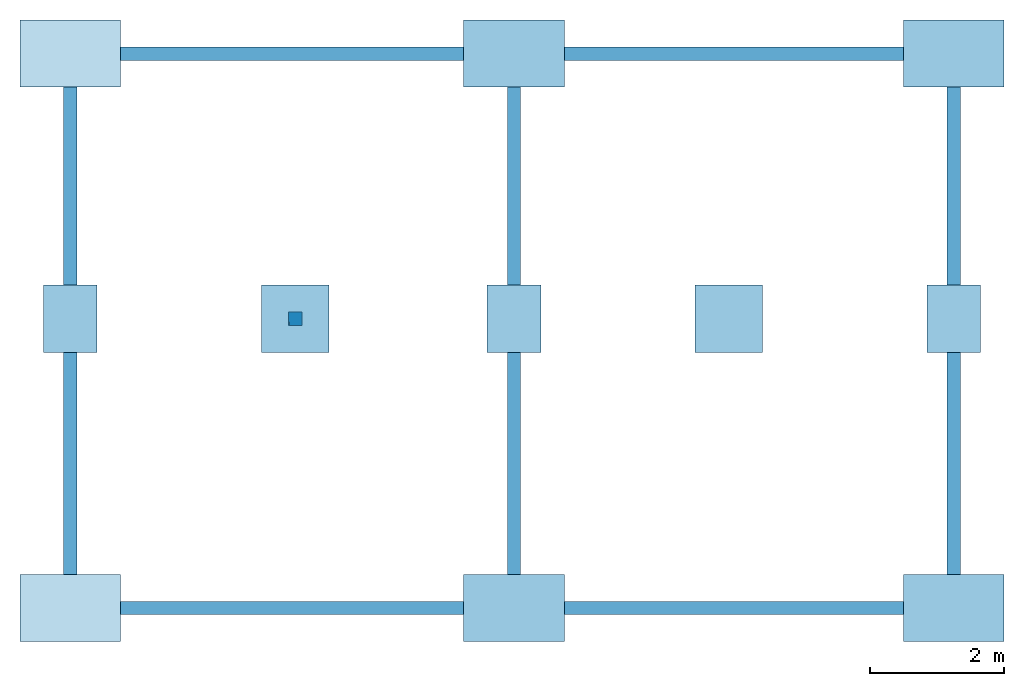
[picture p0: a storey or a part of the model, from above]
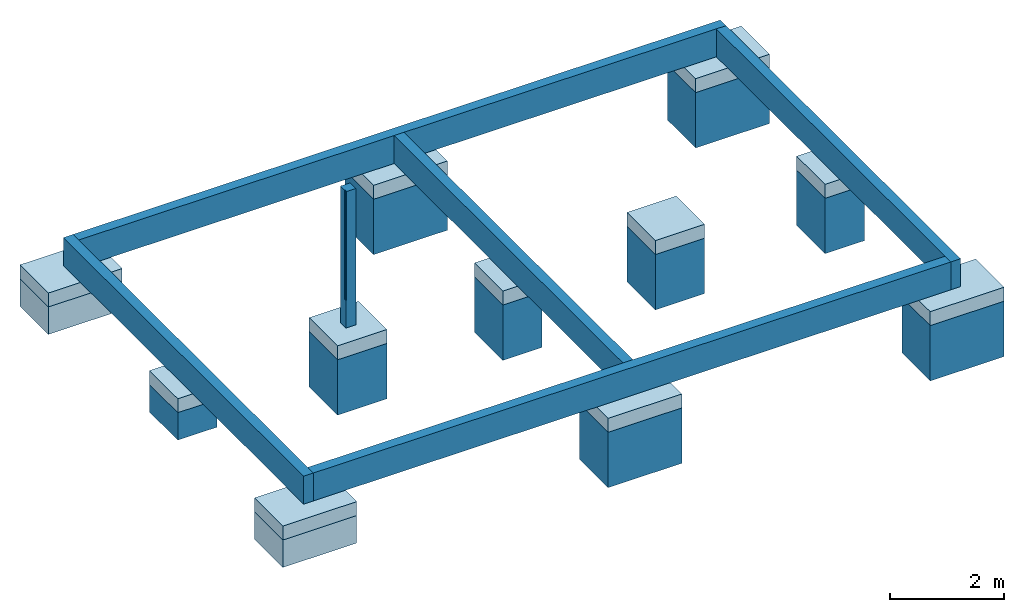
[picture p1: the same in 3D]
Properties of the parts of a building model (IFC2X3)

# File
Description: ViewDefinition [CoordinationView]
Time: 2021-03-23T14:54:17
Made in: SketchUp Pro 2015

# IfcProject, Default Project
Description: Description of Default Project

# IfcSite, Surface:187648
Description: Description of Object; RefLatitude: 24, 28, 0; RefLongitude: 54, 25, 0; RefElevation: 10 mm
Generic - Name: S; CompositionType: c

# IfcBuilding, Default Building
Description: Description of Default Building

# IfcBuildingStorey (4)
In: Default Building
Description: Description of Default Building Storey; Elevation: 0 mm
Name
Plan de couverture
Plan étage
Rez de chaussée
soubassement

# IfcBeam (2)
In: Rez de chaussée
Description: Description of Object
ObjectType - IfcLabel: Poutre rectangulaire - Béton:200 x 400 mm:273551
PSet_BeamCommon - Reference: 200 x 400 mm; Span: 6.53; Slope: 0; isExternal: no; isLoadBearing: yes
Name (IfcBeam - Poutre rectangulaire - Béton:200 x 400 mm:...) | IfcLabel
275096 | Poutre rectangulaire - Béton:200 x 400 mm:275096
274924 | Poutre rectangulaire - Béton:200 x 400 mm:274924

# IfcBuildingElementProxy, IfcBuildingElementProxy - Plafond composé:Plafond avec isolation:277230
In: Plan étage
Description: Description of Object
CompositionType - IfcElementCompositionEnum: complex
ObjectType - IfcLabel: Plafond composé:Plafond avec isolation
Name - IfcLabel: Plafond composé:Plafond avec isolation:277230
Pset_CoveringCommon - Reference: Plafond avec isolation; TotalThickness: 260

# IfcColumn (2)
Description: Description of Object
ObjectType - IfcLabel: 200 x 200 mm
PSet_ColumnCommon - Reference: 200 x 200 mm; isExternal: no; isLoadBearing: no
Name (IfcColumn - Poteau rectangulaire:200 x 200 mm:...) | In | IfcLabel
187492 | Rez de chaussée | Poteau rectangulaire:200 x 200 mm:187492
187471 | soubassement | Poteau rectangulaire:200 x 200 mm:187471

# IfcDoor (26)
Description: Description of Object
PSet_DoorCommon - isExternal: no
Name | In | ObjectType, IfcLabel = Reference | Name, IfcLabel
IfcDoor - Int. Simple:PP (0.83m x 2.04m):187647 | Plan étage | PP (0.83m x 2.04m) | Int. Simple:PP (0.83m x 2.04m):187647
IfcDoor - Int. Simple:PP (0.83m x 2.04m):187644 | Plan étage | PP (0.83m x 2.04m) | Int. Simple:PP (0.83m x 2.04m):187644
IfcDoor - Int. Simple:PP (0.83m x 2.04m):187641 | Plan étage | PP (0.83m x 2.04m) | Int. Simple:PP (0.83m x 2.04m):187641
IfcDoor - Int. Simple:PP (0.83m x 2.04m):187636 | Plan étage | PP (0.83m x 2.04m) | Int. Simple:PP (0.83m x 2.04m):187636
IfcDoor - Int. Simple:PP (0.83m x 2.04m):187635 | Plan étage | PP (0.83m x 2.04m) | Int. Simple:PP (0.83m x 2.04m):187635
IfcDoor - Int. Simple:PP (0.83m x 2.04m):187633 | Plan étage | PP (0.83m x 2.04m) | Int. Simple:PP (0.83m x 2.04m):187633
IfcDoor - Int. Simple:PP (0.83m x 2.04m):187632 | Plan étage | PP (0.83m x 2.04m) | Int. Simple:PP (0.83m x 2.04m):187632
IfcDoor - Int. Simple:PP (0.83m x 2.04m):187631 | Plan étage | PP (0.83m x 2.04m) | Int. Simple:PP (0.83m x 2.04m):187631
IfcDoor - Int. Simple:PP (0.83m x 2.04m):187630 | Plan étage | PP (0.83m x 2.04m) | Int. Simple:PP (0.83m x 2.04m):187630
IfcDoor - Int. Simple:PP (0.83m x 2.04m):187629 | Plan étage | PP (0.83m x 2.04m) | Int. Simple:PP (0.83m x 2.04m):187629
IfcDoor - Int. Simple:PP (0.83m x 2.04m):206630 | Rez de chaussée | PP (0.83m x 2.04m) | Int. Simple:PP (0.83m x 2.04m):206630
IfcDoor - Int. Simple:PP (0.83m x 2.04m):206587 | Rez de chaussée | PP (0.83m x 2.04m) | Int. Simple:PP (0.83m x 2.04m):206587
IfcDoor - Int. Simple:PP (0.83m x 2.04m):206556 | Rez de chaussée | PP (0.83m x 2.04m) | Int. Simple:PP (0.83m x 2.04m):206556
IfcDoor - Int. Simple:PP (0.83m x 2.04m):206517 | Rez de chaussée | PP (0.83m x 2.04m) | Int. Simple:PP (0.83m x 2.04m):206517
IfcDoor - Int. Simple:PP (0.83m x 2.04m):206475 | Rez de chaussée | PP (0.83m x 2.04m) | Int. Simple:PP (0.83m x 2.04m):206475
IfcDoor - Int. Simple:PP (0.83m x 2.04m):206419 | Rez de chaussée | PP (0.83m x 2.04m) | Int. Simple:PP (0.83m x 2.04m):206419
IfcDoor - Double-Glass 1_no trim:PF 1.30 x 2.15:206001 | Rez de chaussée | PF 1.30 x 2.15 | Double-Glass 1_no trim:PF 1.30 x 2.15:206001
IfcDoor - Double-Glass 1_no trim:PF 1.30 x 2.15:205958 | Rez de chaussée | PF 1.30 x 2.15 | Double-Glass 1_no trim:PF 1.30 x 2.15:205958
IfcDoor - Double-Glass 1_no trim:PF 1.30 x 2.15:205926 | Rez de chaussée | PF 1.30 x 2.15 | Double-Glass 1_no trim:PF 1.30 x 2.15:205926
IfcDoor - Double-Glass 1_no trim:PF 1.30 x 2.15:205899 | Rez de chaussée | PF 1.30 x 2.15 | Double-Glass 1_no trim:PF 1.30 x 2.15:205899
IfcDoor - Porte d'entrée:PP Lisse (0.90m x 2.15m):205515 | Rez de chaussée | PP Lisse (0.90m x 2.15m) | Porte d'entrée:PP Lisse (0.90m x 2.15m):205515
IfcDoor - Double-Glass 1_no trim:PF 1.60 x 2.15:205435 | Rez de chaussée | PF 1.60 x 2.15 | Double-Glass 1_no trim:PF 1.60 x 2.15:205435
IfcDoor - Double-Glass 1_no trim:PF 1.60 x 2.15:205161 | Rez de chaussée | PF 1.60 x 2.15 | Double-Glass 1_no trim:PF 1.60 x 2.15:205161
IfcDoor - Placard coulissante - 3 panneaux:Placard coulissante - 3 panneaux:204080 | Rez de chaussée | Placard coulissante - 3 panneaux | Placard coulissante - 3 panneaux:Placard coulissante - 3 panneaux:204080
IfcDoor - Placard coulissante - 3 panneaux:Placard coulissante - 3 panneaux:187537 | Rez de chaussée | Placard coulissante - 3 panneaux | Placard coulissante - 3 panneaux:Placard coulissante - 3 panneaux:187537
IfcDoor - Porte d'entrée:PP Lisse (0.90m x 2.15m):187528 | Rez de chaussée | PP Lisse (0.90m x 2.15m) | Porte d'entrée:PP Lisse (0.90m x 2.15m):187528

# IfcRailing (3)
In: Rez de chaussée
Description: Description of Object
PredefinedType - IfcRailingTypeEnum: handrail
ObjectType - IfcLabel: Garde-corps:Type Bateau
PSet_RailingCommon - Reference: Type Bateau; isExternal: no
Name (IfcRailing - Garde-corps:Type Bateau:...) | IfcLabel
271948 | Garde-corps:Type Bateau:271948
227138 | Garde-corps:Type Bateau:227138
223490 | Garde-corps:Type Bateau:223490

# IfcSlab (27)
Description: Description of Object
PredefinedType - IfcSlabTypeEnum: floor
PSet_SlabCommon - isLoadBearing: yes
Name | In | ObjectType, IfcLabel | Name, IfcLabel | Reference | PitchAngle | isExternal
2 x IfcSlab - Toit de base:Toit - 200 mm:277896 | Plan de couverture | Toit de base:Toit - 200 mm | Toit de base:Toit - 200 mm:277896 | Toit - 200 mm | 31 | yes
IfcSlab - Sol:Dalle Béton -160 + 60 mm:276078 | Plan étage | Sol:Dalle Béton -160 + 60 mm | Sol:Dalle Béton -160 + 60 mm:276078 | Dalle Béton -160 + 60 mm | 0 | no
IfcSlab - Sol:Dalle en béton - 13:220152 | Rez de chaussée | Sol:Dalle en béton - 13 | Sol:Dalle en béton - 13:220152 | Dalle en béton - 13 | 0 | no
IfcSlab - Sol:Dalle en béton - 13:219665 | Rez de chaussée | Sol:Dalle en béton - 13 | Sol:Dalle en béton - 13:219665 | Dalle en béton - 13 | 0 | no
IfcSlab - Base rectangulaire:gros beton 1000mm x 800mm x 1190mm:218905 | soubassement | Base rectangulaire:gros beton 1000mm x 800mm x 1190mm | Base rectangulaire:gros beton 1000mm x 800mm x 1190mm:218905 | gros beton 1000mm x 800mm x 1190mm | 0 | no
IfcSlab - Base rectangulaire:gros beton 1000mm x 800mm x 1190mm:218791 | soubassement | Base rectangulaire:gros beton 1000mm x 800mm x 1190mm | Base rectangulaire:gros beton 1000mm x 800mm x 1190mm:218791 | gros beton 1000mm x 800mm x 1190mm | 0 | no
IfcSlab - Base rectangulaire:gros beton 1000mm x 800mm x 590mm:218621 | soubassement | Base rectangulaire:gros beton 1000mm x 800mm x 590mm | Base rectangulaire:gros beton 1000mm x 800mm x 590mm:218621 | gros beton 1000mm x 800mm x 590mm | 0 | no
IfcSlab - Base rectangulaire:gros beton 1500mm x 1000mm x 1190mm:218347 | soubassement | Base rectangulaire:gros beton 1500mm x 1000mm x 1190mm | Base rectangulaire:gros beton 1500mm x 1000mm x 1190mm:218347 | gros beton 1500mm x 1000mm x 1190mm | 0 | no
IfcSlab - Base rectangulaire:gros beton 1500mm x 1000mm x 590mm:217617 | soubassement | Base rectangulaire:gros beton 1500mm x 1000mm x 590mm | Base rectangulaire:gros beton 1500mm x 1000mm x 590mm:217617 | gros beton 1500mm x 1000mm x 590mm | 0 | no
IfcSlab - Base rectangulaire:gros beton 1500mm x 1000mm x 1190mm:217483 | soubassement | Base rectangulaire:gros beton 1500mm x 1000mm x 1190mm | Base rectangulaire:gros beton 1500mm x 1000mm x 1190mm:217483 | gros beton 1500mm x 1000mm x 1190mm | 0 | no
IfcSlab - Base rectangulaire:gros beton 1500mm x 1000mm x 1190mm:217251 | soubassement | Base rectangulaire:gros beton 1500mm x 1000mm x 1190mm | Base rectangulaire:gros beton 1500mm x 1000mm x 1190mm:217251 | gros beton 1500mm x 1000mm x 1190mm | 0 | no
IfcSlab - Base rectangulaire:gros beton 1500mm x 1000mm x 1190mm:217089 | soubassement | Base rectangulaire:gros beton 1500mm x 1000mm x 1190mm | Base rectangulaire:gros beton 1500mm x 1000mm x 1190mm:217089 | gros beton 1500mm x 1000mm x 1190mm | 0 | no
IfcSlab - Base rectangulaire:gros beton 1500mm x 1000mm x 590mm:216937 | soubassement | Base rectangulaire:gros beton 1500mm x 1000mm x 590mm | Base rectangulaire:gros beton 1500mm x 1000mm x 590mm:216937 | gros beton 1500mm x 1000mm x 590mm | 0 | no
IfcSlab - Base rectangulaire:gros beton 1000mm x 1000mm x 1190mm:216665 | soubassement | Base rectangulaire:gros beton 1000mm x 1000mm x 1190mm | Base rectangulaire:gros beton 1000mm x 1000mm x 1190mm:216665 | gros beton 1000mm x 1000mm x 1190mm | 0 | no
IfcSlab - Base rectangulaire:gros beton 1000mm x 1000mm x 1190mm:216552 | soubassement | Base rectangulaire:gros beton 1000mm x 1000mm x 1190mm | Base rectangulaire:gros beton 1000mm x 1000mm x 1190mm:216552 | gros beton 1000mm x 1000mm x 1190mm | 0 | no
IfcSlab - Base rectangulaire:1000mm x 1000mm x 300mm:215662 | soubassement | Base rectangulaire:1000mm x 1000mm x 300mm | Base rectangulaire:1000mm x 1000mm x 300mm:215662 | 1000mm x 1000mm x 300mm | 0 | no
IfcSlab - Base rectangulaire:1000mm x 1000mm x 300mm:215258 | soubassement | Base rectangulaire:1000mm x 1000mm x 300mm | Base rectangulaire:1000mm x 1000mm x 300mm:215258 | 1000mm x 1000mm x 300mm | 0 | no
IfcSlab - Base rectangulaire:800mm x 1000mm x 300mm:214724 | soubassement | Base rectangulaire:800mm x 1000mm x 300mm | Base rectangulaire:800mm x 1000mm x 300mm:214724 | 800mm x 1000mm x 300mm | 0 | no
IfcSlab - Base rectangulaire:800mm x 1000mm x 300mm:214606 | soubassement | Base rectangulaire:800mm x 1000mm x 300mm | Base rectangulaire:800mm x 1000mm x 300mm:214606 | 800mm x 1000mm x 300mm | 0 | no
IfcSlab - Base rectangulaire:800mm x 1000mm x 300mm:214496 | soubassement | Base rectangulaire:800mm x 1000mm x 300mm | Base rectangulaire:800mm x 1000mm x 300mm:214496 | 800mm x 1000mm x 300mm | 0 | no
IfcSlab - Base rectangulaire:1500mm x 1000mm x 300mm:214106 | soubassement | Base rectangulaire:1500mm x 1000mm x 300mm | Base rectangulaire:1500mm x 1000mm x 300mm:214106 | 1500mm x 1000mm x 300mm | 0 | no
IfcSlab - Base rectangulaire:1500mm x 1000mm x 300mm:214012 | soubassement | Base rectangulaire:1500mm x 1000mm x 300mm | Base rectangulaire:1500mm x 1000mm x 300mm:214012 | 1500mm x 1000mm x 300mm | 0 | no
IfcSlab - Base rectangulaire:1500mm x 1000mm x 300mm:213876 | soubassement | Base rectangulaire:1500mm x 1000mm x 300mm | Base rectangulaire:1500mm x 1000mm x 300mm:213876 | 1500mm x 1000mm x 300mm | 0 | no
IfcSlab - Base rectangulaire:1500mm x 1000mm x 300mm:213688 | soubassement | Base rectangulaire:1500mm x 1000mm x 300mm | Base rectangulaire:1500mm x 1000mm x 300mm:213688 | 1500mm x 1000mm x 300mm | 0 | no
IfcSlab - Base rectangulaire:1500mm x 1000mm x 300mm:213606 | soubassement | Base rectangulaire:1500mm x 1000mm x 300mm | Base rectangulaire:1500mm x 1000mm x 300mm:213606 | 1500mm x 1000mm x 300mm | 0 | no
IfcSlab - Base rectangulaire:1500mm x 1000mm x 300mm:213384 | soubassement | Base rectangulaire:1500mm x 1000mm x 300mm | Base rectangulaire:1500mm x 1000mm x 300mm:213384 | 1500mm x 1000mm x 300mm | 0 | no

# IfcStair (2)
In: Rez de chaussée
Description: Description of Object
ShapeType - IfcStairTypeEnum: straight_run_stair
ObjectType - IfcLabel: Escalier:Monobloc:28673
Name (IfcStair - Escalier:Monobloc:...) | IfcLabel
271926 | Escalier:Monobloc:271926
225808 | Escalier:Monobloc:225808

# IfcWallStandardCase (51)
Description: Description of Object
Name (IfcWallStandardCase - Mur de base:...) | In | ObjectType, IfcLabel | Name, IfcLabel | Reference | ExtendToStructure | isExternal = isLoadBearing
Mur de base Ext. Parpaing 20:278265 | Plan de couverture | Mur de base:Mur de base Ext. Parpaing 20:278331 | Mur de base:Mur de base Ext. Parpaing 20:278265 | Mur de base Ext. Parpaing 20 | yes | yes
Mur de base Ext. Parpaing 20:278254 | Plan de couverture | Mur de base:Mur de base Ext. Parpaing 20:278331 | Mur de base:Mur de base Ext. Parpaing 20:278254 | Mur de base Ext. Parpaing 20 | yes | yes
Mur de base Ext. Parpaing 20 + Isolant 12:188923 | Plan étage | Mur de base:Mur de base Ext. Parpaing 20 + Isolant 12:187234 | Mur de base:Mur de base Ext. Parpaing 20 + Isolant 12:188923 | Mur de base Ext. Parpaing 20 + Isolant 12 | no | yes
Mur de base Ext. Parpaing 20 + Isolant 12:188922 | Plan étage | Mur de base:Mur de base Ext. Parpaing 20 + Isolant 12:187234 | Mur de base:Mur de base Ext. Parpaing 20 + Isolant 12:188922 | Mur de base Ext. Parpaing 20 + Isolant 12 | no | yes
Int. plâtre 50 mm:187646 | Plan étage | Mur de base:Int. plâtre 50 mm:29323 | Mur de base:Int. plâtre 50 mm:187646 | Int. plâtre 50 mm | no | no
Int. plâtre 50 mm:187645 | Plan étage | Mur de base:Int. plâtre 50 mm:29323 | Mur de base:Int. plâtre 50 mm:187645 | Int. plâtre 50 mm | no | no
Int. plâtre 50 mm:187643 | Plan étage | Mur de base:Int. plâtre 50 mm:29323 | Mur de base:Int. plâtre 50 mm:187643 | Int. plâtre 50 mm | no | no
Int. plâtre 50 mm:187642 | Plan étage | Mur de base:Int. plâtre 50 mm:29323 | Mur de base:Int. plâtre 50 mm:187642 | Int. plâtre 50 mm | no | no
Int. plâtre 50 mm:187640 | Plan étage | Mur de base:Int. plâtre 50 mm:29323 | Mur de base:Int. plâtre 50 mm:187640 | Int. plâtre 50 mm | no | no
Int. plâtre 50 mm:187639 | Plan étage | Mur de base:Int. plâtre 50 mm:29323 | Mur de base:Int. plâtre 50 mm:187639 | Int. plâtre 50 mm | no | no
Int. plâtre 50 mm:187638 | Plan étage | Mur de base:Int. plâtre 50 mm:29323 | Mur de base:Int. plâtre 50 mm:187638 | Int. plâtre 50 mm | no | no
Int. plâtre 50 mm:187637 | Plan étage | Mur de base:Int. plâtre 50 mm:29323 | Mur de base:Int. plâtre 50 mm:187637 | Int. plâtre 50 mm | no | no
Int. plâtre 50 mm:187634 | Plan étage | Mur de base:Int. plâtre 50 mm:29323 | Mur de base:Int. plâtre 50 mm:187634 | Int. plâtre 50 mm | no | no
Int. plâtre 50 mm:187628 | Plan étage | Mur de base:Int. plâtre 50 mm:29323 | Mur de base:Int. plâtre 50 mm:187628 | Int. plâtre 50 mm | no | no
Int. plâtre 50 mm:187627 | Plan étage | Mur de base:Int. plâtre 50 mm:29323 | Mur de base:Int. plâtre 50 mm:187627 | Int. plâtre 50 mm | no | no
Int. plâtre 50 mm:187626 | Plan étage | Mur de base:Int. plâtre 50 mm:29323 | Mur de base:Int. plâtre 50 mm:187626 | Int. plâtre 50 mm | no | no
Int. plâtre 50 mm:187625 | Plan étage | Mur de base:Int. plâtre 50 mm:29323 | Mur de base:Int. plâtre 50 mm:187625 | Int. plâtre 50 mm | no | no
Int. plâtre 50 mm:187624 | Plan étage | Mur de base:Int. plâtre 50 mm:29323 | Mur de base:Int. plâtre 50 mm:187624 | Int. plâtre 50 mm | no | no
Int. plâtre 50 mm:187623 | Plan étage | Mur de base:Int. plâtre 50 mm:29323 | Mur de base:Int. plâtre 50 mm:187623 | Int. plâtre 50 mm | no | no
Int. plâtre 50 mm:187622 | Plan étage | Mur de base:Int. plâtre 50 mm:29323 | Mur de base:Int. plâtre 50 mm:187622 | Int. plâtre 50 mm | no | no
Int. plâtre 50 mm:187621 | Plan étage | Mur de base:Int. plâtre 50 mm:29323 | Mur de base:Int. plâtre 50 mm:187621 | Int. plâtre 50 mm | no | no
Int. plâtre 50 mm:187620 | Plan étage | Mur de base:Int. plâtre 50 mm:29323 | Mur de base:Int. plâtre 50 mm:187620 | Int. plâtre 50 mm | no | no
Mur de base Refend Ext. Parpaing 20 + Isolant 7:187610 | Plan étage | Mur de base:Mur de base Refend Ext. Parpaing 20 + Isolant 7:187479 | Mur de base:Mur de base Refend Ext. Parpaing 20 + Isolant 7:187610 | Mur de base Refend Ext. Parpaing 20 + Isolant 7 | no | yes
Mur de base Ext. Parpaing 20 + Isolant 12:187583 | Plan étage | Mur de base:Mur de base Ext. Parpaing 20 + Isolant 12:187234 | Mur de base:Mur de base Ext. Parpaing 20 + Isolant 12:187583 | Mur de base Ext. Parpaing 20 + Isolant 12 | no | yes
Mur de base Ext. Parpaing 20 + Isolant 12:187561 | Plan étage | Mur de base:Mur de base Ext. Parpaing 20 + Isolant 12:187234 | Mur de base:Mur de base Ext. Parpaing 20 + Isolant 12:187561 | Mur de base Ext. Parpaing 20 + Isolant 12 | no | yes
Int. plâtre 50 mm:187536 | Rez de chaussée | Mur de base:Int. plâtre 50 mm:29323 | Mur de base:Int. plâtre 50 mm:187536 | Int. plâtre 50 mm | no | no
Int. plâtre 50 mm:187535 | Rez de chaussée | Mur de base:Int. plâtre 50 mm:29323 | Mur de base:Int. plâtre 50 mm:187535 | Int. plâtre 50 mm | no | no
Int. plâtre 50 mm:187534 | Rez de chaussée | Mur de base:Int. plâtre 50 mm:29323 | Mur de base:Int. plâtre 50 mm:187534 | Int. plâtre 50 mm | no | no
Int. plâtre 50 mm:187533 | Rez de chaussée | Mur de base:Int. plâtre 50 mm:29323 | Mur de base:Int. plâtre 50 mm:187533 | Int. plâtre 50 mm | no | no
Int. plâtre 50 mm:187532 | Rez de chaussée | Mur de base:Int. plâtre 50 mm:29323 | Mur de base:Int. plâtre 50 mm:187532 | Int. plâtre 50 mm | no | no
Int. plâtre 50 mm:187531 | Rez de chaussée | Mur de base:Int. plâtre 50 mm:29323 | Mur de base:Int. plâtre 50 mm:187531 | Int. plâtre 50 mm | no | no
Int. plâtre 50 mm:187522 | Rez de chaussée | Mur de base:Int. plâtre 50 mm:29323 | Mur de base:Int. plâtre 50 mm:187522 | Int. plâtre 50 mm | no | no
Int. plâtre 50 mm:187521 | Rez de chaussée | Mur de base:Int. plâtre 50 mm:29323 | Mur de base:Int. plâtre 50 mm:187521 | Int. plâtre 50 mm | no | no
Int. plâtre 50 mm:187520 | Rez de chaussée | Mur de base:Int. plâtre 50 mm:29323 | Mur de base:Int. plâtre 50 mm:187520 | Int. plâtre 50 mm | no | no
Int. plâtre 50 mm:187519 | Rez de chaussée | Mur de base:Int. plâtre 50 mm:29323 | Mur de base:Int. plâtre 50 mm:187519 | Int. plâtre 50 mm | no | no
Int. plâtre 50 mm:187518 | Rez de chaussée | Mur de base:Int. plâtre 50 mm:29323 | Mur de base:Int. plâtre 50 mm:187518 | Int. plâtre 50 mm | no | no
Int. plâtre 50 mm:187517 | Rez de chaussée | Mur de base:Int. plâtre 50 mm:29323 | Mur de base:Int. plâtre 50 mm:187517 | Int. plâtre 50 mm | no | no
Mur de base Refend Ext. Parpaing 20 + Isolant 7:187506 | Rez de chaussée | Mur de base:Mur de base Refend Ext. Parpaing 20 + Isolant 7:187479 | Mur de base:Mur de base Refend Ext. Parpaing 20 + Isolant 7:187506 | Mur de base Refend Ext. Parpaing 20 + Isolant 7 | no | yes
Mur de base Ext. Parpaing 20 + Isolant 12:187495 | Rez de chaussée | Mur de base:Mur de base Ext. Parpaing 20 + Isolant 12:187234 | Mur de base:Mur de base Ext. Parpaing 20 + Isolant 12:187495 | Mur de base Ext. Parpaing 20 + Isolant 12 | no | yes
Mur de base Ext. Parpaing 20 + Isolant 12:187494 | Rez de chaussée | Mur de base:Mur de base Ext. Parpaing 20 + Isolant 12:187234 | Mur de base:Mur de base Ext. Parpaing 20 + Isolant 12:187494 | Mur de base Ext. Parpaing 20 + Isolant 12 | no | yes
Int. plâtre 50 mm:187440 | Rez de chaussée | Mur de base:Int. plâtre 50 mm:29323 | Mur de base:Int. plâtre 50 mm:187440 | Int. plâtre 50 mm | no | no
Int. plâtre 50 mm:187425 | Rez de chaussée | Mur de base:Int. plâtre 50 mm:29323 | Mur de base:Int. plâtre 50 mm:187425 | Int. plâtre 50 mm | no | no
Mur de base Ext. Parpaing 20 + Isolant 12:187389 | Rez de chaussée | Mur de base:Mur de base Ext. Parpaing 20 + Isolant 12:187234 | Mur de base:Mur de base Ext. Parpaing 20 + Isolant 12:187389 | Mur de base Ext. Parpaing 20 + Isolant 12 | no | yes
Mur de base Ext. Parpaing 20 + Isolant 12:187353 | Rez de chaussée | Mur de base:Mur de base Ext. Parpaing 20 + Isolant 12:187234 | Mur de base:Mur de base Ext. Parpaing 20 + Isolant 12:187353 | Mur de base Ext. Parpaing 20 + Isolant 12 | no | yes
Int. plâtre 50 mm:187338 | Rez de chaussée | Mur de base:Int. plâtre 50 mm:29323 | Mur de base:Int. plâtre 50 mm:187338 | Int. plâtre 50 mm | no | no
Int. plâtre 50 mm:187323 | Rez de chaussée | Mur de base:Int. plâtre 50 mm:29323 | Mur de base:Int. plâtre 50 mm:187323 | Int. plâtre 50 mm | no | no
Ext. longrine 20 x 60:212556 | soubassement | Mur de base:Ext. longrine 20 x 60:212299 | Mur de base:Ext. longrine 20 x 60:212556 | Ext. longrine 20 x 60 | no | yes
Ext. longrine 20 x 60:212434 | soubassement | Mur de base:Ext. longrine 20 x 60:212299 | Mur de base:Ext. longrine 20 x 60:212434 | Ext. longrine 20 x 60 | no | yes
Ext. longrine 20 x 60:212399 | soubassement | Mur de base:Ext. longrine 20 x 60:212299 | Mur de base:Ext. longrine 20 x 60:212399 | Ext. longrine 20 x 60 | no | yes
Ext. longrine 20 x 60:212358 | soubassement | Mur de base:Ext. longrine 20 x 60:212299 | Mur de base:Ext. longrine 20 x 60:212358 | Ext. longrine 20 x 60 | no | yes
Ext. longrine 20 x 60:212326 | soubassement | Mur de base:Ext. longrine 20 x 60:212299 | Mur de base:Ext. longrine 20 x 60:212326 | Ext. longrine 20 x 60 | no | yes

# IfcWindow (8)
In: Plan étage
Description: Description of Object
PSet_WindowCommon - isExternal: yes
Name (IfcWindow - FR_1 Vantail Appui Béton:...) | ObjectType, IfcLabel = Reference | Name, IfcLabel
60x65:220469 | 60x65 | FR_1 Vantail Appui Béton:60x65:220469
90x135:220425 | 90x135 | FR_1 Vantail Appui Béton:90x135:220425
90x135:220372 | 90x135 | FR_1 Vantail Appui Béton:90x135:220372
90x135:220338 | 90x135 | FR_1 Vantail Appui Béton:90x135:220338
90x135:220312 | 90x135 | FR_1 Vantail Appui Béton:90x135:220312
90x135:220285 | 90x135 | FR_1 Vantail Appui Béton:90x135:220285
60x65:190471 | 60x65 | FR_1 Vantail Appui Béton:60x65:190471
90x135:190443 | 90x135 | FR_1 Vantail Appui Béton:90x135:190443
